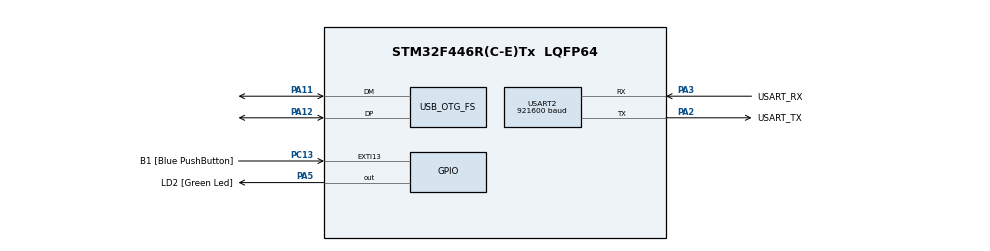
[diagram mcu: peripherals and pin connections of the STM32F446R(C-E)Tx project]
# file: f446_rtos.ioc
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Mcu.Family=STM32F4
Mcu.Name=STM32F446R(C-E)Tx
Mcu.Package=LQFP64
NVIC.PriorityGroup=NVIC_PRIORITYGROUP_4
NVIC.USART2_IRQn=true\:6\:0\:true\:false\:true\:true\:true\:true
PA11.Mode=Device_Only
PA11.Signal=USB_OTG_FS_DM
PA12.Mode=Device_Only
PA12.Signal=USB_OTG_FS_DP
PA13.GPIO_Label=TMS
PA13.Mode=Serial_Wire
PA13.Signal=SYS_JTMS-SWDIO
PA14.GPIO_Label=TCK
PA14.Mode=Serial_Wire
PA14.Signal=SYS_JTCK-SWCLK
PA2.GPIO_Label=USART_TX
PA2.Mode=Asynchronous
PA2.Signal=USART2_TX
PA3.GPIO_Label=USART_RX
PA3.Mode=Asynchronous
PA3.Signal=USART2_RX
PA5.GPIO_Label=LD2 [Green Led]
PA5.Signal=GPIO_Output
PB3.GPIO_Label=SWO
PB3.Signal=SYS_JTDO-SWO
PC13.GPIO_Label=B1 [Blue PushButton]
PC13.GPIO_ModeDefaultEXTI=GPIO_MODE_IT_FALLING
PC13.Signal=GPXTI13
PC14-OSC32_IN.Mode=LSE-External-Oscillator
PC14-OSC32_IN.Signal=RCC_OSC32_IN
PC15-OSC32_OUT.Mode=LSE-External-Oscillator
PC15-OSC32_OUT.Signal=RCC_OSC32_OUT
PH0-OSC_IN.Mode=HSE-External-Oscillator
PH0-OSC_IN.Signal=RCC_OSC_IN
PH1-OSC_OUT.Mode=HSE-External-Oscillator
PH1-OSC_OUT.Signal=RCC_OSC_OUT
ProjectManager.HeapSize=0x200
ProjectManager.StackSize=0x400
ProjectManager.TargetToolchain=STM32CubeIDE
RCC.48MHZClocksFreq_Value=84000000
RCC.AHBFreq_Value=168000000
RCC.APB1CLKDivider=RCC_HCLK_DIV4
RCC.APB1Freq_Value=42000000
RCC.APB1TimFreq_Value=84000000
RCC.APB2CLKDivider=RCC_HCLK_DIV4
RCC.APB2Freq_Value=42000000
RCC.APB2TimFreq_Value=84000000
RCC.CortexFreq_Value=168000000
RCC.FLatency-AdvancedSettings=FLASH_LATENCY_5
RCC.HCLKFreq_Value=168000000
RCC.HSE_VALUE=8000000
RCC.HSI_VALUE=16000000
RCC.PLLM=8
RCC.PLLN=336
RCC.PLLQ=7
RCC.PLLSourceVirtual=RCC_PLLSOURCE_HSE
RCC.SYSCLKFreq_VALUE=168000000
RCC.SYSCLKSource=RCC_SYSCLKSOURCE_PLLCLK
RCC.USBFreq_Value=48000000
RCC.VCOOutputFreq_Value=336000000
USART2.BaudRate=921600
USART2.VirtualMode=VM_ASYNC
USB_OTG_FS.VirtualMode=Device_Only
board=NUCLEO-F446RE

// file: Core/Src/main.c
/* USER CODE BEGIN Header */
/**
  ******************************************************************************
  * @file           : main.c
  * @brief          : Main program body
  ******************************************************************************
  * @attention
  *
  * Copyright (c) 2026 STMicroelectronics.
  * All rights reserved.
  *
  * This software is licensed under terms that can be found in the LICENSE file
  * in the root directory of this software component.
  * If no LICENSE file comes with this software, it is provided AS-IS.
  *
  ******************************************************************************
  */
/* USER CODE END Header */
#include "main.h"
#include "usart.h"
#include "usb_otg.h"
#include "gpio.h"

/* USER CODE BEGIN Includes */
#include <stdlib.h>
#include <stdarg.h>
#include <stdio.h>
#include <string.h>
#include "rtos.h"
#include "rtos_usb.h"
#include "asm_test.h"
#include "ai_app.h"
#include "selftest.h"
#include "benchmark.h"
#if FIRMWARE_AUDIT
#include "audit_regressions.h"
#endif
/* boundary_test.h 只在 HIL 夹具目录(hil\fw\Inc)存在, 而该目录仅由
 * hil\build_fw.ps1 -Variant boundary 加入头文件搜索路径。用 __has_include
 * 兜住: 日常/CubeIDE 构建不会因为缺少这个可选夹具头而编译失败。 */
#if defined(__has_include)
#if __has_include("boundary_test.h")
#include "boundary_test.h"
#endif
#else
#include "boundary_test.h"
#endif
#if FIRMWARE_SCENARIO
#include "test_scenarios.h"
#endif
#if FIRMWARE_PRODUCTION_STRESS
#include "production_stress.h"
#endif
/* USER CODE END Includes */

/* USER CODE BEGIN PD */

/* ======================================================================
 * 固件形态选择(HIL 测试编排开关)
 *
 * 默认(不传任何 -D)= 日常演示固件: 应用任务 + HardFault 测试任务 + USB。
 * 测试固件由 hil\build_fw.ps1 传入 -DFIRMWARE_xxx=1 选择, 每一种都只
 * 启用被测任务, 以保证测量期间没有其它任务竞争 CPU(测量口径要求)。
 * 命令行定义优先于这里的默认值(#ifndef 保护)。
 * ====================================================================== */
#ifndef FIRMWARE_USB_APP
#define FIRMWARE_USB_APP        1   /* USB 协议栈 + CDC/MSC/HID 应用任务 */
#endif
#ifndef FIRMWARE_FAULT_TASKS
#define FIRMWARE_FAULT_TASKS    1   /* 1~9 级 HardFault 测试任务 */
#endif
#ifndef FIRMWARE_APP_TASKS
#define FIRMWARE_APP_TASKS      1   /* task0/1/uart/algo 演示任务 */
#endif
#ifndef FIRMWARE_SELFTEST
#define FIRMWARE_SELFTEST       0   /* Core/Src/selftest.c 全量功能回归 */
#endif
#ifndef FIRMWARE_BENCH
#define FIRMWARE_BENCH          0   /* Core/Src/benchmark.c 性能微基准 */
#endif
#ifndef FIRMWARE_BOUNDARY
#define FIRMWARE_BOUNDARY       0   /* hil/fw/boundary_test.c 边界夹具 */
#endif
#ifndef FIRMWARE_SCENARIO
#define FIRMWARE_SCENARIO       0   /* 系统级场景对比夹具(0 表示不启用) */
#endif
#ifndef FIRMWARE_PRODUCTION_STRESS
#define FIRMWARE_PRODUCTION_STRESS 0
#endif

/* USER CODE END PD */

/* USER CODE BEGIN PV */
#if FIRMWARE_SELFTEST
static rtos_tcb_t *selftest_tcb;
#endif
#if FIRMWARE_BENCH
static rtos_tcb_t *bench_tcb;
#endif
#if FIRMWARE_BOUNDARY
static rtos_tcb_t *boundary_tcb;
#endif
#if FIRMWARE_SCENARIO
static rtos_tcb_t *scenario_tcb;
#endif
#if FIRMWARE_PRODUCTION_STRESS
static rtos_tcb_t *production_stress_tcb;
#endif
/* USER CODE END PV */

void SystemClock_Config(void);
/* USER CODE BEGIN PFP */
static uint8_t ft_dispatch(uint8_t byte);   /* 故障测试命令分发(定义在 ft_* 任务之后) */
/* USER CODE END PFP */

/* USER CODE BEGIN 0 */
int _write(int file, char *ptr, int len)
{
    (void)file;

    HAL_UART_Transmit(&huart2, (uint8_t *)ptr, len, 1000);

    return len;
}

void itm_printf(char *fmt, ...)
{
    va_list args;
    char str[128];
    int len;

    va_start(args, fmt);
    len = vsprintf(str, fmt, args);
    for (int i = 0; i < len; i++) {
        ITM_SendChar(str[i]);
    }
    va_end(args);
}

static rtos_tcb_t      *task_tcb;

static void task_0(void *arg)
{
    uint32_t cnt = 0;
    (void)arg;

    while (1) {
        printf("task 0 running\r\n");
        // cnt = asm_increment(cnt);
        // cnt = asm_pass_args(cnt, 1, 2, 3, 4);
        // printf("cnt = %d\r\n", cnt);
        // asm_printf("0123456789\r\n");
        (void)cnt;
        rtos_task_delay(1000);
    }
}

static rtos_tcb_t      *task1_tcb;

static void task_1(void *arg)
{
    (void)arg;
    while (1) {
        printf("task 1 running\r\n");
        rtos_task_delay(500);
    }
}

static rtos_event_t     algo_task_event;
static rtos_tcb_t      *task_uart_tcb;
static uint8_t          uart2_queue_storage[4096];
static rtos_queue_t     uart2_rx_queue;
static uint8_t          audio_buf[4096];
static uint16_t         audio_cnt = 0U;
static void task_uart(void *arg)
{
    uint8_t byte;

    (void)arg;
    while (1) {
        /* 队列空则阻塞等待(WAIT_FOREVER), 收到一个字节 */
        if (rtos_queue_recv(&uart2_rx_queue, &byte, RTOS_WAIT_FOREVER) == RTOS_OK) {
            /* HardFault 测试调度: 数字命令通知对应测试任务, 不进音频缓冲 */
            // if (ft_dispatch(byte)) {
            //     continue;
            // }
//            audio_buf[audio_cnt++] = byte;
//            if (audio_cnt >= 2048) {
//                audio_cnt = 0U;
//                rtos_event_set(&algo_task_event, 0x01U);
//            }
        }
    }
}

static rtos_tcb_t      *algo_task_tcb;

static void algo_task(void *arg)
{
    float logits[4];
    uint32_t class_id = 0;

    (void)arg;
    while (1) {
        rtos_event_wait(&algo_task_event, 0x01U, RTOS_EVENT_WAIT_ANY | RTOS_EVENT_CLEAR_ON_EXIT, RTOS_WAIT_FOREVER);
        printf("algo_task running\r\n");

        uint32_t tick = rtos_sched_get_tick_count();
        ai_forward_u8(audio_buf, logits, &class_id);
        switch (class_id) {
            case 0:
                printf("无人声\r\n");
                break;
            case 1:
                printf("其他人\r\n");
                break;
            case 2:
                printf("小原\r\n");
                break;
            case 3:
                printf("小芯\r\n");
                break;
            default:
                printf("未知错误\r\n");
                break;
        }
        printf("algo cost time = %u\r\n", (unsigned)(rtos_sched_get_tick_count() - tick));
    }
}

/* ==================================================================== */
/*          HardFault 诊断验证: 故障触发测试任务                          */
/*                                                                      */
/* 通过 USART2 发送数字选择测试项(每项触发后系统停机, 需复位再做下一项):  */
/*   '1' → 精确总线故障  (BFSR.PRECISERR + BFARVALID + BFAR)             */
/*   '2' → 非法状态故障  (UFSR.INVSTATE, 栈帧 xPSR.T=0)                 */
/*   '3' → 除零故障      (UFSR.DIVBYZERO, 需 CCR.DIV_0_TRP)             */
/*   '4' → 栈边界演示    (margin 报告 + stack_magic 毁坏 + 总线故障)    */
/*   '5' → 未定义指令    (UFSR.UNDEFINSTR, 执行 UDF 编码)               */
/*   '6' → 非对齐访问    (UFSR.UNALIGNED, LDRD 永久禁止非对齐)           */
/*   '7' → 写越界故障    (BFSR, 写缓冲异步 → 常见 IMPRECISERR)          */
/*   '8' → 真实栈溢出    (SP 低于栈底, 专用小栈 + 献祭缓冲)             */
/*   '9' → ISR 内故障    (命令后发任意字节, 验证 Handler 模式帧/IPSR)    */
/* 1~8 各一个任务(同时验证任务归因), 9 在 USART2 ISR 内直接触发。        */
/* ==================================================================== */

static rtos_tcb_t *ft1_tcb;
static rtos_tcb_t *ft2_tcb;
static rtos_tcb_t *ft3_tcb;
static rtos_tcb_t *ft4_tcb;
static rtos_tcb_t *ft5_tcb;
static rtos_tcb_t *ft6_tcb;
static rtos_tcb_t *ft7_tcb;

/* 测试9: ISR 内故障的布防标志('9' 命令置位, 下一字节的 RX 中断触发) */
static volatile uint8_t g_isr_fault_arm = 0U;

/* 测试2 用到的正常函数(地址 bit0=1, 取反后模拟被破坏的函数指针) */
static void ft_noop(void)
{
}

/* ---- 测试1: 精确总线故障 ----
 * 读 RAM 末尾之外的保留地址(读操作是同步的 → PRECISERR, PC/BFAR 可信) */
static void ftask_bus(void *arg)
{
    (void)arg;
    uint32_t v;

    for (;;) {
        rtos_task_notify_wait(RTOS_WAIT_FOREVER, &v);
        printf("[FT1] BusFault: read 0x20020000 (beyond RAM end)\r\n");
        v = *(volatile uint32_t *)0x20020000UL;   /* ← 故障点 */
        (void)v;
    }
}

/* ---- 测试2: 非法状态 ----
 * BLX 到 bit0=0 的地址(非 Thumb) → UFSR.INVSTATE, 栈帧 xPSR.T=0 */
static void ftask_invstate(void *arg)
{
    (void)arg;
    uint32_t v;

    for (;;) {
        rtos_task_notify_wait(RTOS_WAIT_FOREVER, &v);
        printf("[FT2] UsageFault INVSTATE: call non-Thumb address\r\n");
        /* volatile 阻止编译器看穿掩码直接 bl ft_noop */
        volatile uint32_t target = ((uint32_t)ft_noop) & ~1UL;
        ((void (*)(void))target)();             /* ← 故障点 */
    }
}

/* ---- 测试3: 除零 ----
 * CCR.DIV_0_TRP=1 时 UDIV 除零 → UFSR.DIVBYZERO (UsageFault) */
static void ftask_div0(void *arg)
{
    (void)arg;
    uint32_t v;

    for (;;) {
        rtos_task_notify_wait(RTOS_WAIT_FOREVER, &v);
        printf("[FT3] UsageFault DIVBYZERO\r\n");
        volatile uint32_t z = 0U;
        volatile uint32_t r = 100U / z;            /* ← 故障点 */
        (void)r;
    }
}

/* ---- 测试4: 栈边界演示 ----
 * noinline 保证递归每层真实消耗栈; 最深层破坏 TCB.stack_magic 模拟
 * "TCB 被越界写", 随后触发总线故障 → dump 报告 margin 与 magic 报警。 */
static uint32_t __attribute__((noinline)) ft_recurse(uint32_t depth)
{
    volatile char pad[256];                     /* 每层消耗 ~256B */
    pad[0]  = (char)depth;
    pad[255] = (char)(depth + 1U);

    if (depth > 0U) {
        return ft_recurse(depth - 1U) + (uint32_t)(uint8_t)pad[0];
    }

    /* 最深层: 此时任务栈已被消耗大半, dump 的 margin 将明显小于 size */
#if RTOS_CONFIG_CHECK_FOR_STACK_OVERFLOW
    ft4_tcb->stack_magic = 0x12345678U;           /* 模拟 TCB 被越界写破坏 */
#endif
    {
        volatile uint32_t v = *(volatile uint32_t *)0x20020000UL;  /* ← 故障点 */
        (void)v;
    }
    return (uint32_t)(uint8_t)pad[0];
}

static void ftask_stack(void *arg)
{
    (void)arg;
    uint32_t v;

    for (;;) {
        rtos_task_notify_wait(RTOS_WAIT_FOREVER, &v);
        printf("[FT4] stack margin + magic + BusFault\r\n");
        ft_recurse(2U);                         /* 递归 2 层再触发故障 */
    }
}

/* ---- 测试5: 未定义指令 ----
 * .short 0xDE00 = UDF #0 (ARMv7-M 永久未定义的指令编码),
 * 执行到该半字即触发 UsageFault: UFSR.UNDEFINSTR, PC 指向该指令。
 * 模拟场景: 函数指针跑飞落入数据区/代码被改写。 */
static void ftask_undef(void *arg)
{
    (void)arg;
    uint32_t v;

    for (;;) {
        rtos_task_notify_wait(RTOS_WAIT_FOREVER, &v);
        printf("[FT5] UsageFault UNDEFINSTR: execute UDF halfword\r\n");
        __asm volatile(".short 0xDE00");        /* ← 故障点: UDF #0 */
    }
}

/* ---- 测试6: 非对齐访问 ----
 * LDRD 基址必须字对齐, 非 4 整数倍时无条件触发 UsageFault:
 * UFSR.UNALIGNED。与 CCR.UNALIGN_TRP 无关 —— 普通 ldr/str 的非对齐
 * 访问是架构合法操作(仅陷阱开启时才报), 而 ldrd/ldm/stm/ldrex
 * 永久禁止非对齐。 */
static uint8_t ft6_buf[8] = {1, 2, 3, 4, 5, 6, 7, 8};

static void ftask_unaligned(void *arg)
{
    (void)arg;
    uint32_t v;
    uint32_t lo, hi;

    for (;;) {
        rtos_task_notify_wait(RTOS_WAIT_FOREVER, &v);
        printf("[FT6] UsageFault UNALIGNED: ldrd from misaligned address\r\n");
        v = (uint32_t)&ft6_buf[1];              /* 地址 ≡1 (mod 4) 非对齐 */
        __asm volatile("ldrd %0, %1, [%2]" : "=&r"(lo), "=&r"(hi) : "r"(v)); /* ← 故障点 */
        (void)lo;
        (void)hi;
    }
}

/* ---- 测试7: 写越界(非精确总线故障) ----
 * 对 RAM 末尾之外的保留地址写入。写操作经写缓冲异步下发, 总线错误
 * 常在若干条指令之后才回报: BFSR.IMPRECISERR, 此时 PC/BFAR 均不可信
 * (dump 会明确提示"不可信"), 用于验证非精确路径的呈现。
 * 注: 部分总线实现可能报 PRECISERR, 亦属正常。 */
static void ftask_imprecise(void *arg)
{
    (void)arg;
    uint32_t v;

    for (;;) {
        rtos_task_notify_wait(RTOS_WAIT_FOREVER, &v);
        printf("[FT7] BusFault write 0x20020000 (imprecise expected)\r\n");
        *(volatile uint32_t *)0x20020000UL = 0x12345678U;   /* ← 故障点 */
    }
}

/* ---- 测试8: 真实栈溢出 ----
 * 专用 512B 小栈: 递归 4 层 ×(160B 垫片+帧) ≈ 800B, SP 深入栈底之下
 * 数百字节, 再触发总线故障 → dump 报告 "*** SP已低于栈底: 栈溢出! ***"
 * 及真实(负)margin。献祭区声明在栈数组之前(典型 .bss 布局下位于其低
 * 地址侧), 吸收溢出写入以保护其他静态数据; 极端布局下输出可能失真,
 * 但故障本身仍会被捕获。 */
static rtos_tcb_t  ft8_tcb;
static uint32_t    ft8_guard[128];                /* 512B 献祭缓冲 */
static rtos_stack_t ft8_stack[128];               /* 512B 任务栈 */

static uint32_t __attribute__((noinline)) ft_recurse8(uint32_t depth)
{
    volatile char pad[160];                       /* 每层 ~160B + 帧开销 */

    pad[0]   = (char)depth;
    pad[159] = (char)(depth + 1U);

    if (depth > 0U) {
        return ft_recurse8(depth - 1U) + (uint32_t)(uint8_t)pad[0];
    }

    /* 最深层: SP 已低于 ft8_stack 栈底, 处于献祭区内 */
    {
        volatile uint32_t v = *(volatile uint32_t *)0x20020000UL;   /* ← 故障点 */
        (void)v;
    }
    return (uint32_t)(uint8_t)pad[0];
}

static void ftask_overflow(void *arg)
{
    (void)arg;
    uint32_t v;

    /* 献祭区仅被动接收溢出写入, 无需显式访问; 引用一次消除未用警告 */
    (void)ft8_guard;

    for (;;) {
        rtos_task_notify_wait(RTOS_WAIT_FOREVER, &v);
        printf("[FT8] real stack overflow: recurse 4x160B in 512B stack\r\n");
        ft_recurse8(3U);                        /* 递归 4 层(3→0) */
    }
}

/* UART 数字命令 → 通知对应测试任务触发故障; 返回 1 表示命令已消费 */
static uint8_t ft_dispatch(uint8_t byte)
{
    switch (byte) {
        case '1':
            rtos_task_notify(ft1_tcb, 1U, RTOS_NOTIFY_VALUE);
            return 1U;
        case '2':
            rtos_task_notify(ft2_tcb, 1U, RTOS_NOTIFY_VALUE);
            return 1U;
        case '3':
            rtos_task_notify(ft3_tcb, 1U, RTOS_NOTIFY_VALUE);
            return 1U;
        case '4':
            rtos_task_notify(ft4_tcb, 1U, RTOS_NOTIFY_VALUE);
            return 1U;
        case '5':
            rtos_task_notify(ft5_tcb, 1U, RTOS_NOTIFY_VALUE);
            return 1U;
        case '6':
            rtos_task_notify(ft6_tcb, 1U, RTOS_NOTIFY_VALUE);
            return 1U;
        case '7':
            rtos_task_notify(ft7_tcb, 1U, RTOS_NOTIFY_VALUE);
            return 1U;
        case '8':
            rtos_task_notify(&ft8_tcb, 1U, RTOS_NOTIFY_VALUE);
            return 1U;
        case '9':
            g_isr_fault_arm = 1U;   /* 再发任意字节即在 ISR 内触发 */
            return 1U;
        default:
            return 0U;
    }
}

uint8_t g_uart2_rx;
void HAL_UART_RxCpltCallback(UART_HandleTypeDef *huart)
{
    /* RTOS 自测试: 消费触发字节 'X' 并在真实 ISR 上下文执行 API 矩阵 */
    if (selftest_uart_isr_hook(g_uart2_rx)) {
        HAL_UART_Receive_IT(&huart2, (uint8_t *)&g_uart2_rx, 1);
        return;
    }

    /* HardFault 测试9: 命令 '9' 布防后, 在本回调(USART2 中断上下文)内
     * 触发总线故障。用于验证 Handler 模式故障路径:
     * EXC_RETURN bit3=0(帧压在 MSP)、dump 提示"错误发生在 ISR 内"、
     * 栈帧 IPSR 报出被打断的异常号(USART2 = 16+38 = 54)。 */
    if (g_isr_fault_arm != 0U) {
        g_isr_fault_arm = 0U;
        volatile uint32_t v = *(volatile uint32_t *)0x20020000UL;   /* ← ISR 内故障点 */
        (void)v;
    }

    HAL_UART_Receive_IT(&huart2, (uint8_t *)&g_uart2_rx, 1);
    /* ISR 中发送必须 RTOS_NO_WAIT; 队列按值拷贝单字节 */
    rtos_queue_send(&uart2_rx_queue, &g_uart2_rx, RTOS_NO_WAIT, RTOS_FALSE);
}

/* ==================================================================== */
/*          USB 任务: 虚拟串口(CDC) + 大容量存储(MSC)                     */
/*                                                                      */
/* 设备为复合设备: 插入主机后同时枚举出                                  */
/*   - 一个虚拟串口(CDC ACM, 可用串口助手收发)                           */
/*   - 一个 U 盘(MSC RAM 盘, 首次使用需在主机端格式化)                   */
/* 初始化在 main() 中完成(rtos_usb_init + rtos_usb_cdc_init),           */
/* MSC 的 SCSI 处理由 CherryUSB 内部线程(usbd_msc)完成。                */
/* ==================================================================== */

static rtos_tcb_t *usb_cdc_tcb;

/* CDC 任务: 虚拟串口回显。主机打开串口并发送的数据会被原样发回。 */
static void task_usb_cdc(void *arg)
{
    uint8_t buf[64];
    bool banner_sent = false;

    (void)arg;
    while (1) {
        if (!rtos_usb_cdc_is_connected(0)) {
            banner_sent = false;
            rtos_task_delay(100);
            continue;
        }

        /* 每次连接后发一次欢迎信息 */
        if (!banner_sent) {
            static const char banner[] = "RTOS USB CDC ready\r\n";
            rtos_usb_cdc_write(0, (const uint8_t *)banner, sizeof(banner) - 1U, 1000);
            banner_sent = true;
        }

        /* 阻塞等待主机数据(1s 超时), 收到后原样回显 */
        int n = rtos_usb_cdc_read(0, buf, sizeof(buf), 1000);
        if (n > 0) {
            rtos_usb_cdc_write(0, buf, (uint32_t)n, 1000);
        }
    }
}

static rtos_tcb_t *usb_msc_tcb;

/* MSC 任务: 监视 U 盘扇区读写统计, 有变化时经 USART2 打印。
 * (实际 SCSI 读写由 CherryUSB 的 usbd_msc 内部线程处理,
 *  本任务仅做状态观测, 也可在此挂接文件系统等扩展逻辑) */
static void task_usb_msc(void *arg)
{
    uint32_t last_reads = 0, last_writes = 0;
    uint32_t reads, writes;

    (void)arg;
    while (1) {
        rtos_task_delay(2000);
        rtos_usb_msc_get_stats(0, &reads, &writes);
        if ((reads != last_reads) || (writes != last_writes)) {
            printf("[MSC] sectors read=%u write=%u\r\n", (unsigned)reads, (unsigned)writes);
            last_reads = reads;
            last_writes = writes;
        }
    }
}

static rtos_tcb_t *usb_hid_tcb;

/* HID 任务: 自定义厂商定义 HID 设备(64B IN/OUT 报告)。
 *  - 每秒发送一个 Input 报告: [0]=0x5A 魔术字, [1]=序号, [2..5]=系统 tick
 *  - 主机发来的 Output 报告原样回显, 并经 USART2 打印提示
 * 主机侧可用 hidapi 或 CherryUSB 的 test_hid_inout.py 测试。 */
static void task_usb_hid(void *arg)
{
    uint8_t in_rep[64];
    uint8_t out_rep[64];
    uint8_t seq = 0U;

    (void)arg;
    while (1) {
        rtos_task_delay(1000);
        if (!rtos_usb_cdc_is_connected(0)) {
            continue; /* 复合设备未完成枚举(同一设备的 CDC 连接标志) */
        }

        /* 非阻塞检查主机是否发来 Output 报告, 有则回显 + 打印 */
        int n = rtos_usb_hid_read(0, out_rep, sizeof(out_rep), 0);
        if (n > 0) {
            rtos_usb_hid_write(0, out_rep, (uint32_t)n, 1000);
            printf("[HID] out report recv %d bytes, echoed\r\n", n);
        }

        /* 周期性 Input 报告 */
        memset(in_rep, 0, sizeof(in_rep));
        in_rep[0] = 0x5AU;
        in_rep[1] = seq++;
        uint32_t tick = rtos_sched_get_tick_count();
        memcpy(&in_rep[2], &tick, sizeof(tick));
        rtos_usb_hid_write(0, in_rep, sizeof(in_rep), 1000);
    }
}
/* USER CODE END 0 */

int main(void)
{

  /* MCU Configuration--------------------------------------------------------*/

  /* Reset of all peripherals, Initializes the Flash interface and the Systick. */
  HAL_Init();

  /* Configure the system clock */
  SystemClock_Config();

  /* Initialize all configured peripherals */
  MX_GPIO_Init();
  MX_USART2_UART_Init();
  /* USER CODE BEGIN 2 */
  /* HardFault 诊断前置(设计文档: docs/hardfault_debug.md):
   * 1. 使能三类可配置故障 —— 否则所有错误升级为 HardFault 且 CFSR 不留记录,
   *    错误分别进入 UsageFault/BusFault/MemManage Handler(已接入诊断模块)。
   * 2. DIV_0_TRP: 把静默除零(默认返回0)变成可定位故障(测试3需要)。
   * 3. ★ 不开启 UNALIGN_TRP: 普通 ldr/str 的非对齐访问在 M3/M4/M7 上是
   *    架构支持的合法操作(GCC 的 store-merging 会主动生成之), 开启陷阱
   *    会误伤正常代码甚至故障处理自身(2026-08 真机事故); 需要
   *    UFSR.UNALIGNED 时用 ldrd/ldm 类永久禁止非对齐的指令触发(测试6)。 */
  SCB->SHCSR |= (7UL << 16);                     /* USAGEFAULTENA | BUSFAULTENA | MEMFAULTENA */
  SCB->CCR   |= SCB_CCR_DIV_0_TRP_Msk;

  /* 注意: 不要调用 MX_USB_OTG_FS_PCD_Init()。USB 内核寄存器由 CherryUSB
   * DWC2 驱动(usb_dc_dwc2.c)接管, HAL PCD 只复用其 MspInit 做 48MHz 时钟/
   * GPIO/中断初始化(由 rtos_usb_cdc_init 内部的 usb_dc_init 触发)。
   * 若调用 HAL_PCD_Init 会与 DWC2 驱动抢占同一组 USB 寄存器。 */
  rtos_queue_init(&uart2_rx_queue, uart2_queue_storage, 1, sizeof(uart2_queue_storage));
  HAL_UART_Receive_IT(&huart2, (uint8_t *)&g_uart2_rx, 1);

  rtos_event_init(&algo_task_event);
  printf("System init done\r\n");
  printf("[FAULT-TEST] send '1'..'9' via USART2 (each test halts, reset between):\r\n");
  printf("  1: BusFault    precise read  @0x20020000\r\n");
  printf("  2: INVSTATE    call non-Thumb address\r\n");
  printf("  3: DIVBYZERO   (DIV_0_TRP enabled)\r\n");
  printf("  4: stack demo  (margin + magic + BusFault)\r\n");
  printf("  5: UNDEFINSTR  execute UDF halfword\r\n");
  printf("  6: UNALIGNED ldrd misaligned (always faults)\r\n");
  printf("  7: BusFault    write @0x20020000 (imprecise expected)\r\n");
  printf("  8: real stack overflow (SP below base)\r\n");
  printf("  9: fault inside USART2 ISR (send '9', then any byte)\r\n");

  rtos_init();
#if FIRMWARE_AUDIT
  audit_pre_start();
#endif

#if FIRMWARE_SELFTEST
  /* 阶段1 必须在调度器启动前由 main 上下文执行(见 selftest.h 契约)。
   * 漏掉这一句会导致 phase2 首句 rtos_task_delete(NULL) 变成自删, 测试卡死
   * (踩坑记录: .trae/scenario_test/HANDOFF.md 第 1 节)。 */
  selftest_pre_start();
#endif

  /* 恢复日常固件形态: 应用任务 + USB(内核已含全部修复与性能优化,
   * selftest/benchmark 固件按需启用, 见 Core/Src/selftest.c 与 benchmark.c) */
#if FIRMWARE_USB_APP
  rtos_usb_init();
  rtos_usb_cdc_init(0, (uintptr_t)USB_OTG_FS);
#endif

  /* 系统级场景对比测试期间: 应用任务全部停用, 保证测量期间只有被测任务在跑。 */
#if FIRMWARE_APP_TASKS
  rtos_task_create(&task_tcb, 256, task_0, NULL, 6, "task0");
  rtos_task_create(&task1_tcb, 256, task_1, NULL, 5, "task1");
  rtos_task_create(&task_uart_tcb, 256, task_uart, NULL, 1, "uart");
  rtos_task_create(&algo_task_tcb, 256, algo_task, NULL, 10, "algo");
#endif
#if FIRMWARE_FAULT_TASKS
  /* HardFault 诊断验证任务: 阻塞等待 UART 数字命令后触发对应故障 */
  rtos_task_create(&ft1_tcb, 256, ftask_bus,       NULL, 7, "ft1_bus");
  rtos_task_create(&ft2_tcb, 256, ftask_invstate,  NULL, 7, "ft2_invst");
  rtos_task_create(&ft3_tcb, 256, ftask_div0,      NULL, 7, "ft3_div0");
  rtos_task_create(&ft4_tcb, 256, ftask_stack,     NULL, 7, "ft4_stk");
  rtos_task_create(&ft5_tcb, 256, ftask_undef,     NULL, 7, "ft5_undef");
  rtos_task_create(&ft6_tcb, 256, ftask_unaligned, NULL, 7, "ft6_align");
  rtos_task_create(&ft7_tcb, 256, ftask_imprecise, NULL, 7, "ft7_impr");
  /* 测试8 用静态小栈(512B)+献祭缓冲, 不能用动态大栈 */
  rtos_task_create_static(&ft8_tcb, ft8_stack, 128, ftask_overflow, NULL, 7, "ft8_ovf");
#endif

  /* USB 应用任务: CDC 回显 + MSC 状态监视 + HID 报告收发
   * (优先级 8, 低于 USB 协议栈线程 16) */
#if FIRMWARE_USB_APP
  rtos_task_create(&usb_cdc_tcb, 256, task_usb_cdc, NULL, 8, "usb_cdc");
  rtos_task_create(&usb_msc_tcb, 256, task_usb_msc, NULL, 8, "usb_msc");
  rtos_task_create(&usb_hid_tcb, 256, task_usb_hid, NULL, 8, "usb_hid");
#endif

  /* 测试固件: 每轮只启用一种(HIL 脚本保证互斥) */
#if FIRMWARE_AUDIT
  rtos_tcb_t *audit_tcb;
  rtos_task_create(&audit_tcb, 1024, audit_regressions_task, NULL, 9, "audit");
#endif
#if FIRMWARE_SELFTEST
  rtos_task_create(&selftest_tcb, 1024, selftest_task, NULL, 9, "selftest");
#endif
#if FIRMWARE_BENCH
  rtos_task_create(&bench_tcb, 1024, bench_task, NULL, 9, "bench");
#endif
#if FIRMWARE_BOUNDARY
  rtos_task_create(&boundary_tcb, 1024, boundary_test_task, NULL, 9, "boundary");
#endif
#if FIRMWARE_SCENARIO
  rtos_task_create(&scenario_tcb, 1024, test_scenario_task, NULL, 9, "scenario");
#endif
#if FIRMWARE_PRODUCTION_STRESS
    rtos_status_t stress_status = rtos_task_create(&production_stress_tcb, 1024U,
        production_stress_task, NULL, 4U, "production-stress");
    if (stress_status != RTOS_OK) {
        printf("STRESS|FAIL|controller_create|status=%ld\r\n", (long)stress_status);
        printf("STRESS|DONE|status=%ld\r\n", (long)stress_status);
    }
#endif

  rtos_start();

  /* USER CODE END 2 */

  /* Infinite loop */
  while (1)
  {

  }
}

void SystemClock_Config(void)
{
  RCC_OscInitTypeDef RCC_OscInitStruct = {0};
  RCC_ClkInitTypeDef RCC_ClkInitStruct = {0};

  /** Configure the main internal regulator output voltage
  */
  __HAL_RCC_PWR_CLK_ENABLE();
  __HAL_PWR_VOLTAGESCALING_CONFIG(PWR_REGULATOR_VOLTAGE_SCALE1);

  /** Initializes the RCC Oscillators according to the specified parameters
  * in the RCC_OscInitTypeDef structure.
  */
  RCC_OscInitStruct.OscillatorType = RCC_OSCILLATORTYPE_HSE;
  RCC_OscInitStruct.HSEState = RCC_HSE_ON;
  RCC_OscInitStruct.PLL.PLLState = RCC_PLL_ON;
  RCC_OscInitStruct.PLL.PLLSource = RCC_PLLSOURCE_HSE;
  RCC_OscInitStruct.PLL.PLLM = 8;
  RCC_OscInitStruct.PLL.PLLN = 336;
  RCC_OscInitStruct.PLL.PLLP = RCC_PLLP_DIV2;
  RCC_OscInitStruct.PLL.PLLQ = 7;
  RCC_OscInitStruct.PLL.PLLR = 2;
  if (HAL_RCC_OscConfig(&RCC_OscInitStruct) != HAL_OK)
  {
    Error_Handler();
  }

  /** Initializes the CPU, AHB and APB buses clocks
  */
  RCC_ClkInitStruct.ClockType = RCC_CLOCKTYPE_HCLK|RCC_CLOCKTYPE_SYSCLK
                              |RCC_CLOCKTYPE_PCLK1|RCC_CLOCKTYPE_PCLK2;
  RCC_ClkInitStruct.SYSCLKSource = RCC_SYSCLKSOURCE_PLLCLK;
  RCC_ClkInitStruct.AHBCLKDivider = RCC_SYSCLK_DIV1;
  RCC_ClkInitStruct.APB1CLKDivider = RCC_HCLK_DIV4;
  RCC_ClkInitStruct.APB2CLKDivider = RCC_HCLK_DIV2;

  if (HAL_RCC_ClockConfig(&RCC_ClkInitStruct, FLASH_LATENCY_5) != HAL_OK)
  {
    Error_Handler();
  }
}

void Error_Handler(void)
{
  __disable_irq();
  while (1)
  {
  }
}
